VERSION 5.8 ;
BUSBITCHARS "[]" ;
DIVIDERCHAR "/" ;
UNITS
    DATABASE MICRONS 1000 ;
END UNITS

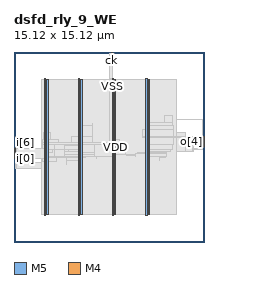
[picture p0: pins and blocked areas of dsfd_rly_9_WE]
MACRO dsfd_rly_9_WE
  FOREIGN dsfd_rly_9_WE 0 0 ;
  CLASS BLOCK ;
  SIZE 15.12 BY 15.12 ;
  PIN ck
    DIRECTION INPUT ;
    USE SIGNAL ;
    PORT
      LAYER M5 ;
        RECT  7.728 15.036 7.752 15.12 ;
    END
  END ck
  PIN i[0]
    DIRECTION INPUT ;
    USE SIGNAL ;
    PORT
      LAYER M4 ;
        RECT  0 6.672 0.084 6.696 ;
    END
  END i[0]
  PIN i[1]
    DIRECTION INPUT ;
    USE SIGNAL ;
    PORT
      LAYER M4 ;
        RECT  0 6.768 0.084 6.792 ;
    END
  END i[1]
  PIN i[2]
    DIRECTION INPUT ;
    USE SIGNAL ;
    PORT
      LAYER M4 ;
        RECT  0 6.864 0.084 6.888 ;
    END
  END i[2]
  PIN i[3]
    DIRECTION INPUT ;
    USE SIGNAL ;
    PORT
      LAYER M4 ;
        RECT  0 6.96 0.084 6.984 ;
    END
  END i[3]
  PIN i[4]
    DIRECTION INPUT ;
    USE SIGNAL ;
    PORT
      LAYER M4 ;
        RECT  0 7.056 0.084 7.08 ;
    END
  END i[4]
  PIN i[5]
    DIRECTION INPUT ;
    USE SIGNAL ;
    PORT
      LAYER M4 ;
        RECT  0 7.152 0.084 7.176 ;
    END
  END i[5]
  PIN i[6]
    DIRECTION INPUT ;
    USE SIGNAL ;
    PORT
      LAYER M4 ;
        RECT  0 7.248 0.084 7.272 ;
    END
  END i[6]
  PIN i[7]
    DIRECTION INPUT ;
    USE SIGNAL ;
    PORT
      LAYER M4 ;
        RECT  0 7.344 0.084 7.368 ;
    END
  END i[7]
  PIN i[8]
    DIRECTION INPUT ;
    USE SIGNAL ;
    PORT
      LAYER M4 ;
        RECT  0 7.44 0.084 7.464 ;
    END
  END i[8]
  PIN o[0]
    DIRECTION OUTPUT ;
    USE SIGNAL ;
    PORT
      LAYER M4 ;
        RECT  15.036 7.632 15.12 7.656 ;
    END
  END o[0]
  PIN o[1]
    DIRECTION OUTPUT ;
    USE SIGNAL ;
    PORT
      LAYER M4 ;
        RECT  15.036 7.728 15.12 7.752 ;
    END
  END o[1]
  PIN o[2]
    DIRECTION OUTPUT ;
    USE SIGNAL ;
    PORT
      LAYER M4 ;
        RECT  15.036 7.824 15.12 7.848 ;
    END
  END o[2]
  PIN o[3]
    DIRECTION OUTPUT ;
    USE SIGNAL ;
    PORT
      LAYER M4 ;
        RECT  15.036 7.92 15.12 7.944 ;
    END
  END o[3]
  PIN o[4]
    DIRECTION OUTPUT ;
    USE SIGNAL ;
    PORT
      LAYER M4 ;
        RECT  15.036 8.016 15.12 8.04 ;
    END
  END o[4]
  PIN o[5]
    DIRECTION OUTPUT ;
    USE SIGNAL ;
    PORT
      LAYER M4 ;
        RECT  15.036 8.112 15.12 8.136 ;
    END
  END o[5]
  PIN o[6]
    DIRECTION OUTPUT ;
    USE SIGNAL ;
    PORT
      LAYER M4 ;
        RECT  15.036 8.208 15.12 8.232 ;
    END
  END o[6]
  PIN o[7]
    DIRECTION OUTPUT ;
    USE SIGNAL ;
    PORT
      LAYER M4 ;
        RECT  15.036 8.304 15.12 8.328 ;
    END
  END o[7]
  PIN o[8]
    DIRECTION OUTPUT ;
    USE SIGNAL ;
    PORT
      LAYER M4 ;
        RECT  15.036 8.4 15.12 8.424 ;
    END
  END o[8]
  PIN rs
    DIRECTION INPUT ;
    USE SIGNAL ;
    PORT
      LAYER M5 ;
        RECT  7.824 15.036 7.848 15.12 ;
    END
  END rs
  PIN VDD
    DIRECTION INOUT ;
    USE POWER ;
    PORT
      LAYER M5 ;
        RECT  10.692 2.151 10.812 12.969 ;
        RECT  7.992 2.151 8.112 12.969 ;
        RECT  5.292 2.151 5.412 12.969 ;
        RECT  2.592 2.151 2.712 12.969 ;
    END
  END VDD
  PIN VSS
    DIRECTION INOUT ;
    USE GROUND ;
    PORT
      LAYER M5 ;
        RECT  10.5 2.137 10.62 12.983 ;
        RECT  7.8 2.137 7.92 12.983 ;
        RECT  5.1 2.137 5.22 12.983 ;
        RECT  2.4 2.137 2.52 12.983 ;
    END
  END VSS
  # OT_OBS_CLOSED layer=M5 d_um=1.536 added=0
  OBS
    LAYER RVTN ;
     RECT  2.16 2.16 12.96 2.295 ;
     RECT  2.16 2.565 12.96 2.835 ;
     RECT  2.16 3.105 12.96 3.375 ;
     RECT  2.16 3.645 12.96 3.915 ;
     RECT  2.16 4.185 12.96 4.455 ;
     RECT  2.16 4.725 12.96 4.995 ;
     RECT  2.16 5.265 12.96 5.535 ;
     RECT  2.16 5.805 12.96 6.075 ;
     RECT  2.16 6.345 12.96 6.615 ;
     RECT  2.16 6.885 12.96 7.155 ;
     RECT  2.16 7.425 12.96 7.695 ;
     RECT  2.16 7.965 12.96 8.235 ;
     RECT  2.16 8.505 12.96 8.775 ;
     RECT  2.16 9.045 12.96 9.315 ;
     RECT  2.16 9.585 12.96 9.855 ;
     RECT  2.16 10.125 12.96 10.395 ;
     RECT  2.16 10.665 12.96 10.935 ;
     RECT  2.16 11.205 12.96 11.475 ;
     RECT  2.16 11.745 12.96 12.015 ;
     RECT  2.16 12.285 12.96 12.555 ;
     RECT  2.16 12.825 12.96 12.96 ;
    LAYER RVTP ;
     RECT  2.16 2.295 12.96 2.565 ;
     RECT  2.16 2.835 12.96 3.105 ;
     RECT  2.16 3.375 12.96 3.645 ;
     RECT  2.16 3.915 12.96 4.185 ;
     RECT  2.16 4.455 12.96 4.725 ;
     RECT  2.16 4.995 12.96 5.265 ;
     RECT  2.16 5.535 12.96 5.805 ;
     RECT  2.16 6.075 12.96 6.345 ;
     RECT  2.16 6.615 12.96 6.885 ;
     RECT  2.16 7.155 12.96 7.425 ;
     RECT  2.16 7.695 12.96 7.965 ;
     RECT  2.16 8.235 12.96 8.505 ;
     RECT  2.16 8.775 12.96 9.045 ;
     RECT  2.16 9.315 12.96 9.585 ;
     RECT  2.16 9.855 12.96 10.125 ;
     RECT  2.16 10.395 12.96 10.665 ;
     RECT  2.16 10.935 12.96 11.205 ;
     RECT  2.16 11.475 12.96 11.745 ;
     RECT  2.16 12.015 12.96 12.285 ;
     RECT  2.16 12.555 12.96 12.825 ;
    LAYER M1 ;
     RECT  2.16 2.151 12.96 12.969 ;
    LAYER M2 ;
     RECT  0.103 6.12 0.139 6.138 ;
     RECT  0.139 5.85 0.175 6.138 ;
     RECT  0.175 5.85 2.16 6.336 ;
     RECT  2.16 2.151 12.96 12.969 ;
     RECT  12.96 7.236 13.667 8.694 ;
     RECT  13.667 7.236 14.243 8.154 ;
     RECT  14.243 7.236 14.279 7.416 ;
     RECT  14.279 7.398 15.035 7.416 ;
     RECT  12.96 9.756 15.035 9.774 ;
    LAYER M3 ;
     RECT  2.415 2.143 2.505 2.413 ;
     RECT  5.115 2.143 5.205 2.413 ;
     RECT  7.815 2.143 7.905 2.413 ;
     RECT  10.515 2.143 10.605 2.413 ;
     RECT  2.415 2.413 2.697 5.881 ;
     RECT  0.144 5.845 0.162 6.115 ;
     RECT  0.108 6.115 0.162 6.313 ;
     RECT  2.415 5.881 2.754 6.385 ;
     RECT  2.304 6.385 2.79 6.421 ;
     RECT  4.176 6.151 4.194 6.511 ;
     RECT  5.115 2.413 5.397 6.511 ;
     RECT  2.304 6.421 3.402 6.691 ;
     RECT  4.176 6.511 5.397 6.691 ;
     RECT  11.556 6.511 11.574 6.691 ;
     RECT  0.108 6.313 0.198 6.797 ;
     RECT  2.304 6.691 5.706 6.808 ;
     RECT  6.552 6.619 6.57 6.808 ;
     RECT  2.304 6.808 6.57 6.809 ;
     RECT  3.996 6.809 6.57 6.811 ;
     RECT  3.996 6.811 6.858 6.817 ;
     RECT  7.815 2.413 8.097 6.817 ;
     RECT  10.515 2.413 10.797 6.817 ;
     RECT  11.556 6.691 12.078 6.817 ;
     RECT  9.648 6.781 9.666 6.853 ;
     RECT  0.144 6.797 0.198 6.893 ;
     RECT  8.964 6.853 9.666 6.925 ;
     RECT  3.996 6.817 8.097 6.961 ;
     RECT  8.892 6.925 9.666 6.961 ;
     RECT  3.996 6.961 9.666 6.989 ;
     RECT  9.648 6.989 9.666 7.051 ;
     RECT  10.515 6.817 12.114 7.051 ;
     RECT  9.648 7.051 12.114 7.079 ;
     RECT  0.18 6.893 0.198 7.085 ;
     RECT  9.828 7.079 12.114 7.151 ;
     RECT  10.515 7.151 12.114 7.195 ;
     RECT  3.996 6.989 8.91 7.223 ;
     RECT  0.324 7.243 0.342 7.373 ;
     RECT  10.515 7.195 12.474 7.393 ;
     RECT  3.996 7.223 8.802 7.655 ;
     RECT  14.256 7.231 14.274 7.661 ;
     RECT  10.515 7.393 12.618 7.735 ;
     RECT  2.304 6.809 3.222 7.771 ;
     RECT  3.996 7.655 8.514 7.771 ;
     RECT  2.304 7.771 8.514 7.889 ;
     RECT  6.984 7.889 7.002 7.925 ;
     RECT  2.304 7.889 3.546 8.159 ;
     RECT  7.815 7.889 8.37 8.159 ;
     RECT  13.68 7.699 14.238 8.159 ;
     RECT  2.304 8.159 3.078 8.195 ;
     RECT  10.515 7.735 12.654 8.311 ;
     RECT  13.644 8.299 13.662 8.311 ;
     RECT  4.536 7.889 6.246 8.429 ;
     RECT  10.224 8.311 13.662 8.429 ;
     RECT  2.34 8.195 2.898 8.699 ;
     RECT  13.644 8.429 13.662 8.699 ;
     RECT  2.34 8.699 2.697 8.735 ;
     RECT  10.224 8.429 12.654 8.969 ;
     RECT  5.115 8.429 6.246 9.239 ;
     RECT  10.515 8.969 12.654 9.239 ;
     RECT  6.228 9.239 6.246 9.419 ;
     RECT  10.515 9.239 12.618 9.509 ;
     RECT  15.012 7.393 15.03 9.779 ;
     RECT  11.952 9.509 12.618 10.049 ;
     RECT  2.415 8.735 2.697 12.707 ;
     RECT  5.115 9.239 5.397 12.707 ;
     RECT  7.815 8.159 8.097 12.707 ;
     RECT  10.515 9.509 10.797 12.707 ;
     RECT  7.815 12.707 7.974 12.749 ;
     RECT  7.815 12.749 7.905 12.865 ;
     RECT  2.415 12.707 2.505 12.977 ;
     RECT  5.115 12.707 5.205 12.977 ;
     RECT  7.776 12.865 7.905 12.977 ;
     RECT  10.515 12.707 10.605 12.977 ;
     RECT  7.776 12.977 7.794 13.133 ;
    LAYER M4 ;
     RECT  0.06 6.672 2.408 7.464 ;
     RECT  2.408 2.148 2.512 12.972 ;
     RECT  2.512 2.418 2.704 12.702 ;
     RECT  2.704 7.152 3.089 7.368 ;
     RECT  3.089 7.344 4.345 7.368 ;
     RECT  4.345 7.2 5.108 7.368 ;
     RECT  5.108 2.148 5.212 12.972 ;
     RECT  5.212 2.418 5.404 12.702 ;
     RECT  5.404 7.104 6.397 7.752 ;
     RECT  7.621 14.976 7.763 15 ;
     RECT  6.397 6.816 7.808 7.752 ;
     RECT  7.765 13.104 7.808 13.128 ;
     RECT  7.808 2.148 7.859 13.128 ;
     RECT  7.859 2.148 7.912 12.972 ;
     RECT  7.912 2.418 8.104 12.702 ;
     RECT  10.508 2.148 10.612 12.972 ;
     RECT  10.612 2.418 10.804 12.702 ;
     RECT  13.093 8.4 13.633 8.424 ;
     RECT  13.633 8.304 13.669 8.424 ;
     RECT  13.669 8.016 14.173 8.424 ;
     RECT  14.173 7.92 14.209 8.424 ;
     RECT  14.209 7.824 14.245 8.424 ;
     RECT  14.245 7.632 15.084 8.424 ;
    LAYER M5 ;
     RECT  2.4 2.137 2.52 2.151 ;
     RECT  5.1 2.137 5.22 2.151 ;
     RECT  7.8 2.137 7.92 2.151 ;
     RECT  10.5 2.137 10.62 2.151 ;
     RECT  0.144 7.189 0.168 7.379 ;
     RECT  7.8 2.151 8.112 7.381 ;
     RECT  2.4 2.151 2.712 12.969 ;
     RECT  5.1 2.151 5.412 12.969 ;
     RECT  7.632 7.381 8.112 12.969 ;
     RECT  10.5 2.151 10.812 12.969 ;
     RECT  2.4 12.969 2.52 12.983 ;
     RECT  5.1 12.969 5.22 12.983 ;
     RECT  7.632 12.969 7.92 12.983 ;
     RECT  10.5 12.969 10.62 12.983 ;
     RECT  7.632 12.983 7.848 15.011 ;
     RECT  7.728 15.011 7.848 15.056 ;
  END
END dsfd_rly_9_WE
END LIBRARY
